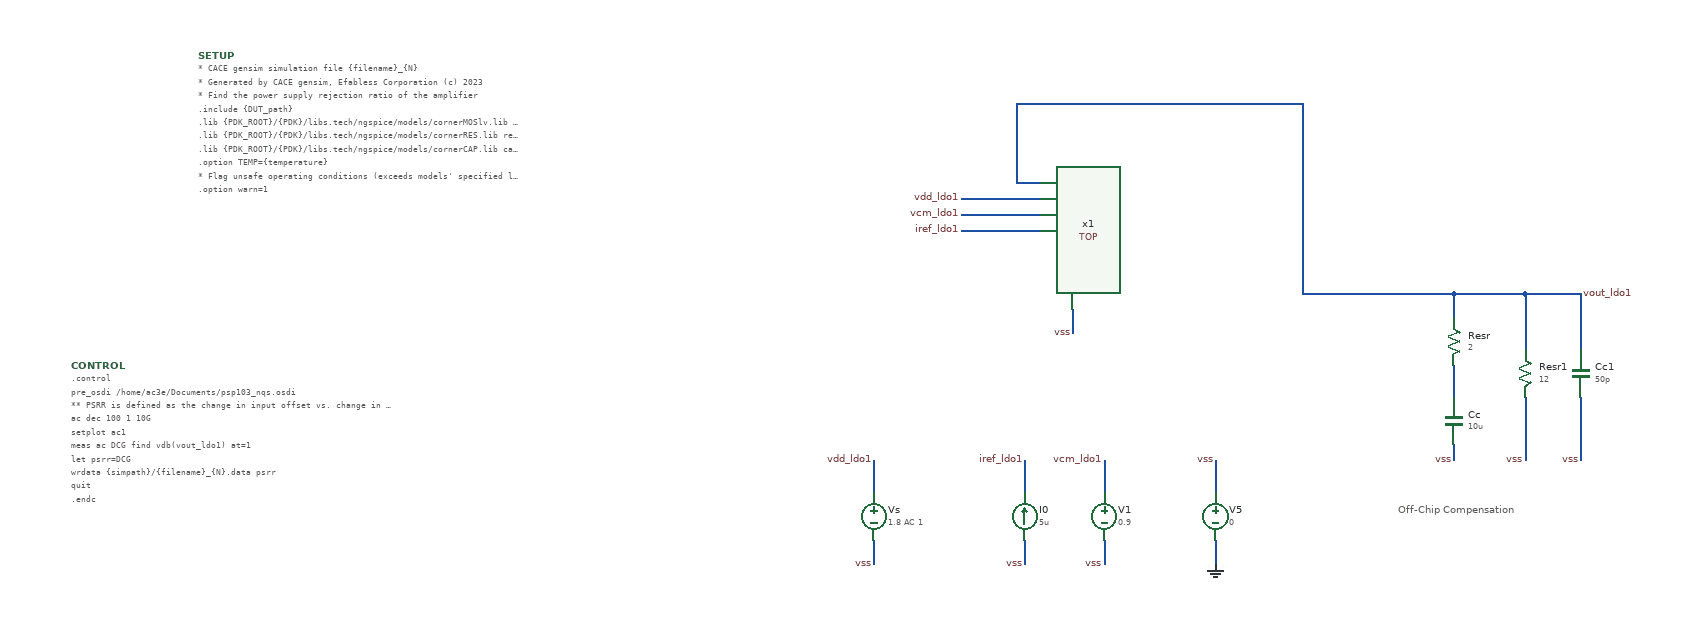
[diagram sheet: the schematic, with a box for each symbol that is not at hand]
v {xschem version=3.4.5 file_version=1.2
}
G {}
K {}
V {}
S {}
E {}
T {Off-Chip Compensation
} -100 -20 3 0 0.4 0.4 {}
N -570 -70 -570 -30 {
lab=iref_ldo1}
N -330 30 -330 60 {
lab=GND}
N -470 30 -470 60 {
lab=vss}
N -570 30 -570 60 {
lab=vss}
N -330 -70 -330 -30 {
lab=vss}
N -470 -70 -470 -30 {
lab=vcm_ldo1}
N -30 -280 -30 -250 {
lab=vout_ldo1}
N -30 -190 -30 -150 {
lab=#net1}
N -30 -90 -30 -70 {
lab=vss}
N -650 -400 -550 -400 {
lab=vdd_ldo1}
N -650 -360 -550 -360 {
lab=iref_ldo1}
N -650 -380 -550 -380 {
lab=vcm_ldo1}
N -510 -260 -510 -230 {
lab=vss}
N -220 -280 -30 -280 {
lab=vout_ldo1}
N 60 -280 60 -210 {
lab=vout_ldo1}
N -30 -280 60 -280 {
lab=vout_ldo1}
N 60 -150 60 -70 {
lab=vss}
N 130 -280 130 -210 {
lab=vout_ldo1}
N 60 -280 130 -280 {
lab=vout_ldo1}
N 130 -150 130 -70 {
lab=vss}
N -220 -520 -220 -280 {
lab=vout_ldo1}
N -580 -520 -220 -520 {
lab=vout_ldo1}
N -580 -520 -580 -420 {
lab=vout_ldo1}
N -580 -420 -550 -420 {
lab=vout_ldo1}
N -760 30 -760 60 {
lab=vss}
N -760 -70 -760 -30 {
lab=vdd_ldo1}
C {devices/vsource.sym} -470 0 0 0 {name=V1 value=0.9 savecurrent=false}
C {devices/vsource.sym} -330 0 0 0 {name=V5 value=0 savecurrent=false}
C {devices/isource.sym} -570 0 2 0 {name=I0 value=5u}
C {devices/lab_pin.sym} -470 60 0 0 {name=p2 sig_type=std_logic lab=vss}
C {devices/gnd.sym} -330 60 0 0 {name=l1 lab=GND}
C {devices/lab_pin.sym} -330 -70 0 0 {name=p5 sig_type=std_logic lab=vss}
C {devices/lab_pin.sym} -510 -230 3 0 {name=p9 sig_type=std_logic lab=vss}
C {devices/lab_pin.sym} -650 -380 0 0 {name=p13 sig_type=std_logic lab=vcm_ldo1}
C {devices/lab_pin.sym} -570 60 0 0 {name=p14 sig_type=std_logic lab=vss}
C {devices/lab_pin.sym} 130 -280 2 0 {name=p15 sig_type=std_logic lab=vout_ldo1}
C {devices/lab_pin.sym} -570 -70 0 0 {name=p12 sig_type=std_logic lab=iref_ldo1}
C {devices/lab_pin.sym} -650 -360 0 0 {name=p17 sig_type=std_logic lab=iref_ldo1}
C {devices/lab_pin.sym} -470 -70 0 0 {name=p18 sig_type=std_logic lab=vcm_ldo1}
C {devices/lab_pin.sym} -650 -400 0 0 {name=p19 sig_type=std_logic lab=vdd_ldo1}
C {devices/capa.sym} -30 -120 0 0 {name=Cc
m=1
value=10u
footprint=1206
device="ceramic capacitor"}
C {devices/res.sym} -30 -220 0 0 {name=Resr
value=2
footprint=1206
device=resistor
m=1}
C {devices/lab_pin.sym} -30 -70 0 0 {name=p4 sig_type=std_logic lab=vss}
C {devices/title.sym} -1000 310 0 0 {name=l2 author="Daniel Arevalos"}
C {devices/lab_pin.sym} 60 -70 0 0 {name=p1 sig_type=std_logic lab=vss}
C {devices/res.sym} 60 -180 0 0 {name=Resr1
value=12
footprint=1206
device=resistor
m=1}
C {devices/capa.sym} 130 -180 0 0 {name=Cc1
m=1
value=50p
footprint=1206
device="ceramic capacitor"}
C {devices/lab_pin.sym} 130 -70 0 0 {name=p3 sig_type=std_logic lab=vss}
C {devices/code_shown.sym} -1610 -580 0 0 {name=SETUP only_toplevel=false value="* CACE gensim simulation file \{filename\}_\{N\}
* Generated by CACE gensim, Efabless Corporation (c) 2023
* Find the power supply rejection ratio of the amplifier

.include \{DUT_path\}

.lib \{PDK_ROOT\}/\{PDK\}/libs.tech/ngspice/models/cornerMOSlv.lib mos_\{corner\}
.lib \{PDK_ROOT\}/\{PDK\}/libs.tech/ngspice/models/cornerRES.lib res_typ
.lib \{PDK_ROOT\}/\{PDK\}/libs.tech/ngspice/models/cornerCAP.lib cap_typ


.option TEMP=\{temperature\}
* Flag unsafe operating conditions (exceeds models' specified limits)
.option warn=1
"}
C {devices/code_shown.sym} -1770 -190 0 0 {name=CONTROL only_toplevel=false value=".control

pre_osdi /home/ac3e/Documents/psp103_nqs.osdi

** PSRR is defined as the change in input offset vs. change in power supply.


ac dec 100 1 10G
setplot ac1
meas ac DCG find vdb(vout_ldo1) at=1
let psrr=DCG

wrdata \{simpath\}/\{filename\}_\{N\}.data psrr
quit
.endc
"}
C {devices/vsource.sym} -760 0 0 0 {name=Vs value="1.8 AC 1" savecurrent=false}
C {devices/lab_pin.sym} -760 60 0 0 {name=p6 sig_type=std_logic lab=vss}
C {devices/lab_pin.sym} -760 -70 0 0 {name=p7 sig_type=std_logic lab=vdd_ldo1}
C {/home/ac3e/Documents/ihp_design/cace/TOP.sym} -450 -360 0 0 {name=x1}
